VERSION 5.7 ;
BUSBITCHARS "[]" ;
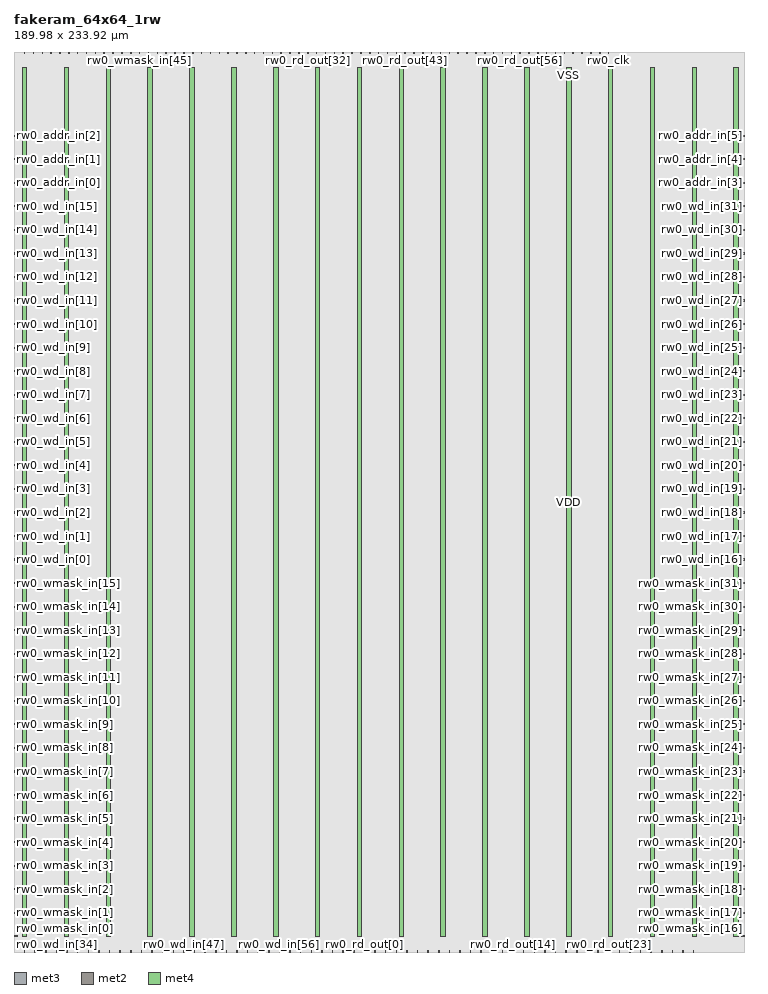
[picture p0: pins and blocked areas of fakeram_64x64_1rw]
MACRO fakeram_64x64_1rw
  FOREIGN fakeram_64x64_1rw 0 0 ;
  SYMMETRY X Y R90 ;
  SIZE 189.980 BY 233.920 ;
  CLASS BLOCK ;
  PIN rw0_wmask_in[0]
    DIRECTION INPUT ;
    USE SIGNAL ;
    SHAPE ABUTMENT ;
    PORT
      LAYER met3 ;
      RECT 0.000 3.930 0.900 4.230 ;
    END
  END rw0_wmask_in[0]
  PIN rw0_wmask_in[1]
    DIRECTION INPUT ;
    USE SIGNAL ;
    SHAPE ABUTMENT ;
    PORT
      LAYER met3 ;
      RECT 0.000 10.050 0.900 10.350 ;
    END
  END rw0_wmask_in[1]
  PIN rw0_wmask_in[2]
    DIRECTION INPUT ;
    USE SIGNAL ;
    SHAPE ABUTMENT ;
    PORT
      LAYER met3 ;
      RECT 0.000 16.170 0.900 16.470 ;
    END
  END rw0_wmask_in[2]
  PIN rw0_wmask_in[3]
    DIRECTION INPUT ;
    USE SIGNAL ;
    SHAPE ABUTMENT ;
    PORT
      LAYER met3 ;
      RECT 0.000 22.290 0.900 22.590 ;
    END
  END rw0_wmask_in[3]
  PIN rw0_wmask_in[4]
    DIRECTION INPUT ;
    USE SIGNAL ;
    SHAPE ABUTMENT ;
    PORT
      LAYER met3 ;
      RECT 0.000 28.410 0.900 28.710 ;
    END
  END rw0_wmask_in[4]
  PIN rw0_wmask_in[5]
    DIRECTION INPUT ;
    USE SIGNAL ;
    SHAPE ABUTMENT ;
    PORT
      LAYER met3 ;
      RECT 0.000 34.530 0.900 34.830 ;
    END
  END rw0_wmask_in[5]
  PIN rw0_wmask_in[6]
    DIRECTION INPUT ;
    USE SIGNAL ;
    SHAPE ABUTMENT ;
    PORT
      LAYER met3 ;
      RECT 0.000 40.650 0.900 40.950 ;
    END
  END rw0_wmask_in[6]
  PIN rw0_wmask_in[7]
    DIRECTION INPUT ;
    USE SIGNAL ;
    SHAPE ABUTMENT ;
    PORT
      LAYER met3 ;
      RECT 0.000 46.770 0.900 47.070 ;
    END
  END rw0_wmask_in[7]
  PIN rw0_wmask_in[8]
    DIRECTION INPUT ;
    USE SIGNAL ;
    SHAPE ABUTMENT ;
    PORT
      LAYER met3 ;
      RECT 0.000 52.890 0.900 53.190 ;
    END
  END rw0_wmask_in[8]
  PIN rw0_wmask_in[9]
    DIRECTION INPUT ;
    USE SIGNAL ;
    SHAPE ABUTMENT ;
    PORT
      LAYER met3 ;
      RECT 0.000 59.010 0.900 59.310 ;
    END
  END rw0_wmask_in[9]
  PIN rw0_wmask_in[10]
    DIRECTION INPUT ;
    USE SIGNAL ;
    SHAPE ABUTMENT ;
    PORT
      LAYER met3 ;
      RECT 0.000 65.130 0.900 65.430 ;
    END
  END rw0_wmask_in[10]
  PIN rw0_wmask_in[11]
    DIRECTION INPUT ;
    USE SIGNAL ;
    SHAPE ABUTMENT ;
    PORT
      LAYER met3 ;
      RECT 0.000 71.250 0.900 71.550 ;
    END
  END rw0_wmask_in[11]
  PIN rw0_wmask_in[12]
    DIRECTION INPUT ;
    USE SIGNAL ;
    SHAPE ABUTMENT ;
    PORT
      LAYER met3 ;
      RECT 0.000 77.370 0.900 77.670 ;
    END
  END rw0_wmask_in[12]
  PIN rw0_wmask_in[13]
    DIRECTION INPUT ;
    USE SIGNAL ;
    SHAPE ABUTMENT ;
    PORT
      LAYER met3 ;
      RECT 0.000 83.490 0.900 83.790 ;
    END
  END rw0_wmask_in[13]
  PIN rw0_wmask_in[14]
    DIRECTION INPUT ;
    USE SIGNAL ;
    SHAPE ABUTMENT ;
    PORT
      LAYER met3 ;
      RECT 0.000 89.610 0.900 89.910 ;
    END
  END rw0_wmask_in[14]
  PIN rw0_wmask_in[15]
    DIRECTION INPUT ;
    USE SIGNAL ;
    SHAPE ABUTMENT ;
    PORT
      LAYER met3 ;
      RECT 0.000 95.730 0.900 96.030 ;
    END
  END rw0_wmask_in[15]
  PIN rw0_wmask_in[16]
    DIRECTION INPUT ;
    USE SIGNAL ;
    SHAPE ABUTMENT ;
    PORT
      LAYER met3 ;
      RECT 189.080 3.930 189.980 4.230 ;
    END
  END rw0_wmask_in[16]
  PIN rw0_wmask_in[17]
    DIRECTION INPUT ;
    USE SIGNAL ;
    SHAPE ABUTMENT ;
    PORT
      LAYER met3 ;
      RECT 189.080 10.050 189.980 10.350 ;
    END
  END rw0_wmask_in[17]
  PIN rw0_wmask_in[18]
    DIRECTION INPUT ;
    USE SIGNAL ;
    SHAPE ABUTMENT ;
    PORT
      LAYER met3 ;
      RECT 189.080 16.170 189.980 16.470 ;
    END
  END rw0_wmask_in[18]
  PIN rw0_wmask_in[19]
    DIRECTION INPUT ;
    USE SIGNAL ;
    SHAPE ABUTMENT ;
    PORT
      LAYER met3 ;
      RECT 189.080 22.290 189.980 22.590 ;
    END
  END rw0_wmask_in[19]
  PIN rw0_wmask_in[20]
    DIRECTION INPUT ;
    USE SIGNAL ;
    SHAPE ABUTMENT ;
    PORT
      LAYER met3 ;
      RECT 189.080 28.410 189.980 28.710 ;
    END
  END rw0_wmask_in[20]
  PIN rw0_wmask_in[21]
    DIRECTION INPUT ;
    USE SIGNAL ;
    SHAPE ABUTMENT ;
    PORT
      LAYER met3 ;
      RECT 189.080 34.530 189.980 34.830 ;
    END
  END rw0_wmask_in[21]
  PIN rw0_wmask_in[22]
    DIRECTION INPUT ;
    USE SIGNAL ;
    SHAPE ABUTMENT ;
    PORT
      LAYER met3 ;
      RECT 189.080 40.650 189.980 40.950 ;
    END
  END rw0_wmask_in[22]
  PIN rw0_wmask_in[23]
    DIRECTION INPUT ;
    USE SIGNAL ;
    SHAPE ABUTMENT ;
    PORT
      LAYER met3 ;
      RECT 189.080 46.770 189.980 47.070 ;
    END
  END rw0_wmask_in[23]
  PIN rw0_wmask_in[24]
    DIRECTION INPUT ;
    USE SIGNAL ;
    SHAPE ABUTMENT ;
    PORT
      LAYER met3 ;
      RECT 189.080 52.890 189.980 53.190 ;
    END
  END rw0_wmask_in[24]
  PIN rw0_wmask_in[25]
    DIRECTION INPUT ;
    USE SIGNAL ;
    SHAPE ABUTMENT ;
    PORT
      LAYER met3 ;
      RECT 189.080 59.010 189.980 59.310 ;
    END
  END rw0_wmask_in[25]
  PIN rw0_wmask_in[26]
    DIRECTION INPUT ;
    USE SIGNAL ;
    SHAPE ABUTMENT ;
    PORT
      LAYER met3 ;
      RECT 189.080 65.130 189.980 65.430 ;
    END
  END rw0_wmask_in[26]
  PIN rw0_wmask_in[27]
    DIRECTION INPUT ;
    USE SIGNAL ;
    SHAPE ABUTMENT ;
    PORT
      LAYER met3 ;
      RECT 189.080 71.250 189.980 71.550 ;
    END
  END rw0_wmask_in[27]
  PIN rw0_wmask_in[28]
    DIRECTION INPUT ;
    USE SIGNAL ;
    SHAPE ABUTMENT ;
    PORT
      LAYER met3 ;
      RECT 189.080 77.370 189.980 77.670 ;
    END
  END rw0_wmask_in[28]
  PIN rw0_wmask_in[29]
    DIRECTION INPUT ;
    USE SIGNAL ;
    SHAPE ABUTMENT ;
    PORT
      LAYER met3 ;
      RECT 189.080 83.490 189.980 83.790 ;
    END
  END rw0_wmask_in[29]
  PIN rw0_wmask_in[30]
    DIRECTION INPUT ;
    USE SIGNAL ;
    SHAPE ABUTMENT ;
    PORT
      LAYER met3 ;
      RECT 189.080 89.610 189.980 89.910 ;
    END
  END rw0_wmask_in[30]
  PIN rw0_wmask_in[31]
    DIRECTION INPUT ;
    USE SIGNAL ;
    SHAPE ABUTMENT ;
    PORT
      LAYER met3 ;
      RECT 189.080 95.730 189.980 96.030 ;
    END
  END rw0_wmask_in[31]
  PIN rw0_wmask_in[32]
    DIRECTION INPUT ;
    USE SIGNAL ;
    SHAPE ABUTMENT ;
    PORT
      LAYER met2 ;
      RECT 2.690 233.500 2.830 233.920 ;
    END
  END rw0_wmask_in[32]
  PIN rw0_wmask_in[33]
    DIRECTION INPUT ;
    USE SIGNAL ;
    SHAPE ABUTMENT ;
    PORT
      LAYER met2 ;
      RECT 4.990 233.500 5.130 233.920 ;
    END
  END rw0_wmask_in[33]
  PIN rw0_wmask_in[34]
    DIRECTION INPUT ;
    USE SIGNAL ;
    SHAPE ABUTMENT ;
    PORT
      LAYER met2 ;
      RECT 7.290 233.500 7.430 233.920 ;
    END
  END rw0_wmask_in[34]
  PIN rw0_wmask_in[35]
    DIRECTION INPUT ;
    USE SIGNAL ;
    SHAPE ABUTMENT ;
    PORT
      LAYER met2 ;
      RECT 9.590 233.500 9.730 233.920 ;
    END
  END rw0_wmask_in[35]
  PIN rw0_wmask_in[36]
    DIRECTION INPUT ;
    USE SIGNAL ;
    SHAPE ABUTMENT ;
    PORT
      LAYER met2 ;
      RECT 11.890 233.500 12.030 233.920 ;
    END
  END rw0_wmask_in[36]
  PIN rw0_wmask_in[37]
    DIRECTION INPUT ;
    USE SIGNAL ;
    SHAPE ABUTMENT ;
    PORT
      LAYER met2 ;
      RECT 14.190 233.500 14.330 233.920 ;
    END
  END rw0_wmask_in[37]
  PIN rw0_wmask_in[38]
    DIRECTION INPUT ;
    USE SIGNAL ;
    SHAPE ABUTMENT ;
    PORT
      LAYER met2 ;
      RECT 16.490 233.500 16.630 233.920 ;
    END
  END rw0_wmask_in[38]
  PIN rw0_wmask_in[39]
    DIRECTION INPUT ;
    USE SIGNAL ;
    SHAPE ABUTMENT ;
    PORT
      LAYER met2 ;
      RECT 18.790 233.500 18.930 233.920 ;
    END
  END rw0_wmask_in[39]
  PIN rw0_wmask_in[40]
    DIRECTION INPUT ;
    USE SIGNAL ;
    SHAPE ABUTMENT ;
    PORT
      LAYER met2 ;
      RECT 21.090 233.500 21.230 233.920 ;
    END
  END rw0_wmask_in[40]
  PIN rw0_wmask_in[41]
    DIRECTION INPUT ;
    USE SIGNAL ;
    SHAPE ABUTMENT ;
    PORT
      LAYER met2 ;
      RECT 23.390 233.500 23.530 233.920 ;
    END
  END rw0_wmask_in[41]
  PIN rw0_wmask_in[42]
    DIRECTION INPUT ;
    USE SIGNAL ;
    SHAPE ABUTMENT ;
    PORT
      LAYER met2 ;
      RECT 25.690 233.500 25.830 233.920 ;
    END
  END rw0_wmask_in[42]
  PIN rw0_wmask_in[43]
    DIRECTION INPUT ;
    USE SIGNAL ;
    SHAPE ABUTMENT ;
    PORT
      LAYER met2 ;
      RECT 27.990 233.500 28.130 233.920 ;
    END
  END rw0_wmask_in[43]
  PIN rw0_wmask_in[44]
    DIRECTION INPUT ;
    USE SIGNAL ;
    SHAPE ABUTMENT ;
    PORT
      LAYER met2 ;
      RECT 30.290 233.500 30.430 233.920 ;
    END
  END rw0_wmask_in[44]
  PIN rw0_wmask_in[45]
    DIRECTION INPUT ;
    USE SIGNAL ;
    SHAPE ABUTMENT ;
    PORT
      LAYER met2 ;
      RECT 32.590 233.500 32.730 233.920 ;
    END
  END rw0_wmask_in[45]
  PIN rw0_wmask_in[46]
    DIRECTION INPUT ;
    USE SIGNAL ;
    SHAPE ABUTMENT ;
    PORT
      LAYER met2 ;
      RECT 34.890 233.500 35.030 233.920 ;
    END
  END rw0_wmask_in[46]
  PIN rw0_wmask_in[47]
    DIRECTION INPUT ;
    USE SIGNAL ;
    SHAPE ABUTMENT ;
    PORT
      LAYER met2 ;
      RECT 37.190 233.500 37.330 233.920 ;
    END
  END rw0_wmask_in[47]
  PIN rw0_wmask_in[48]
    DIRECTION INPUT ;
    USE SIGNAL ;
    SHAPE ABUTMENT ;
    PORT
      LAYER met2 ;
      RECT 39.490 233.500 39.630 233.920 ;
    END
  END rw0_wmask_in[48]
  PIN rw0_wmask_in[49]
    DIRECTION INPUT ;
    USE SIGNAL ;
    SHAPE ABUTMENT ;
    PORT
      LAYER met2 ;
      RECT 41.790 233.500 41.930 233.920 ;
    END
  END rw0_wmask_in[49]
  PIN rw0_wmask_in[50]
    DIRECTION INPUT ;
    USE SIGNAL ;
    SHAPE ABUTMENT ;
    PORT
      LAYER met2 ;
      RECT 44.090 233.500 44.230 233.920 ;
    END
  END rw0_wmask_in[50]
  PIN rw0_wmask_in[51]
    DIRECTION INPUT ;
    USE SIGNAL ;
    SHAPE ABUTMENT ;
    PORT
      LAYER met2 ;
      RECT 46.390 233.500 46.530 233.920 ;
    END
  END rw0_wmask_in[51]
  PIN rw0_wmask_in[52]
    DIRECTION INPUT ;
    USE SIGNAL ;
    SHAPE ABUTMENT ;
    PORT
      LAYER met2 ;
      RECT 48.690 233.500 48.830 233.920 ;
    END
  END rw0_wmask_in[52]
  PIN rw0_wmask_in[53]
    DIRECTION INPUT ;
    USE SIGNAL ;
    SHAPE ABUTMENT ;
    PORT
      LAYER met2 ;
      RECT 50.990 233.500 51.130 233.920 ;
    END
  END rw0_wmask_in[53]
  PIN rw0_wmask_in[54]
    DIRECTION INPUT ;
    USE SIGNAL ;
    SHAPE ABUTMENT ;
    PORT
      LAYER met2 ;
      RECT 53.290 233.500 53.430 233.920 ;
    END
  END rw0_wmask_in[54]
  PIN rw0_wmask_in[55]
    DIRECTION INPUT ;
    USE SIGNAL ;
    SHAPE ABUTMENT ;
    PORT
      LAYER met2 ;
      RECT 55.590 233.500 55.730 233.920 ;
    END
  END rw0_wmask_in[55]
  PIN rw0_wmask_in[56]
    DIRECTION INPUT ;
    USE SIGNAL ;
    SHAPE ABUTMENT ;
    PORT
      LAYER met2 ;
      RECT 57.890 233.500 58.030 233.920 ;
    END
  END rw0_wmask_in[56]
  PIN rw0_wmask_in[57]
    DIRECTION INPUT ;
    USE SIGNAL ;
    SHAPE ABUTMENT ;
    PORT
      LAYER met2 ;
      RECT 60.190 233.500 60.330 233.920 ;
    END
  END rw0_wmask_in[57]
  PIN rw0_wmask_in[58]
    DIRECTION INPUT ;
    USE SIGNAL ;
    SHAPE ABUTMENT ;
    PORT
      LAYER met2 ;
      RECT 62.490 233.500 62.630 233.920 ;
    END
  END rw0_wmask_in[58]
  PIN rw0_wmask_in[59]
    DIRECTION INPUT ;
    USE SIGNAL ;
    SHAPE ABUTMENT ;
    PORT
      LAYER met2 ;
      RECT 64.790 233.500 64.930 233.920 ;
    END
  END rw0_wmask_in[59]
  PIN rw0_wmask_in[60]
    DIRECTION INPUT ;
    USE SIGNAL ;
    SHAPE ABUTMENT ;
    PORT
      LAYER met2 ;
      RECT 67.090 233.500 67.230 233.920 ;
    END
  END rw0_wmask_in[60]
  PIN rw0_wmask_in[61]
    DIRECTION INPUT ;
    USE SIGNAL ;
    SHAPE ABUTMENT ;
    PORT
      LAYER met2 ;
      RECT 69.390 233.500 69.530 233.920 ;
    END
  END rw0_wmask_in[61]
  PIN rw0_wmask_in[62]
    DIRECTION INPUT ;
    USE SIGNAL ;
    SHAPE ABUTMENT ;
    PORT
      LAYER met2 ;
      RECT 71.690 233.500 71.830 233.920 ;
    END
  END rw0_wmask_in[62]
  PIN rw0_wmask_in[63]
    DIRECTION INPUT ;
    USE SIGNAL ;
    SHAPE ABUTMENT ;
    PORT
      LAYER met2 ;
      RECT 73.990 233.500 74.130 233.920 ;
    END
  END rw0_wmask_in[63]
  PIN rw0_wd_in[0]
    DIRECTION INPUT ;
    USE SIGNAL ;
    SHAPE ABUTMENT ;
    PORT
      LAYER met3 ;
      RECT 0.000 101.850 0.900 102.150 ;
    END
  END rw0_wd_in[0]
  PIN rw0_wd_in[1]
    DIRECTION INPUT ;
    USE SIGNAL ;
    SHAPE ABUTMENT ;
    PORT
      LAYER met3 ;
      RECT 0.000 107.970 0.900 108.270 ;
    END
  END rw0_wd_in[1]
  PIN rw0_wd_in[2]
    DIRECTION INPUT ;
    USE SIGNAL ;
    SHAPE ABUTMENT ;
    PORT
      LAYER met3 ;
      RECT 0.000 114.090 0.900 114.390 ;
    END
  END rw0_wd_in[2]
  PIN rw0_wd_in[3]
    DIRECTION INPUT ;
    USE SIGNAL ;
    SHAPE ABUTMENT ;
    PORT
      LAYER met3 ;
      RECT 0.000 120.210 0.900 120.510 ;
    END
  END rw0_wd_in[3]
  PIN rw0_wd_in[4]
    DIRECTION INPUT ;
    USE SIGNAL ;
    SHAPE ABUTMENT ;
    PORT
      LAYER met3 ;
      RECT 0.000 126.330 0.900 126.630 ;
    END
  END rw0_wd_in[4]
  PIN rw0_wd_in[5]
    DIRECTION INPUT ;
    USE SIGNAL ;
    SHAPE ABUTMENT ;
    PORT
      LAYER met3 ;
      RECT 0.000 132.450 0.900 132.750 ;
    END
  END rw0_wd_in[5]
  PIN rw0_wd_in[6]
    DIRECTION INPUT ;
    USE SIGNAL ;
    SHAPE ABUTMENT ;
    PORT
      LAYER met3 ;
      RECT 0.000 138.570 0.900 138.870 ;
    END
  END rw0_wd_in[6]
  PIN rw0_wd_in[7]
    DIRECTION INPUT ;
    USE SIGNAL ;
    SHAPE ABUTMENT ;
    PORT
      LAYER met3 ;
      RECT 0.000 144.690 0.900 144.990 ;
    END
  END rw0_wd_in[7]
  PIN rw0_wd_in[8]
    DIRECTION INPUT ;
    USE SIGNAL ;
    SHAPE ABUTMENT ;
    PORT
      LAYER met3 ;
      RECT 0.000 150.810 0.900 151.110 ;
    END
  END rw0_wd_in[8]
  PIN rw0_wd_in[9]
    DIRECTION INPUT ;
    USE SIGNAL ;
    SHAPE ABUTMENT ;
    PORT
      LAYER met3 ;
      RECT 0.000 156.930 0.900 157.230 ;
    END
  END rw0_wd_in[9]
  PIN rw0_wd_in[10]
    DIRECTION INPUT ;
    USE SIGNAL ;
    SHAPE ABUTMENT ;
    PORT
      LAYER met3 ;
      RECT 0.000 163.050 0.900 163.350 ;
    END
  END rw0_wd_in[10]
  PIN rw0_wd_in[11]
    DIRECTION INPUT ;
    USE SIGNAL ;
    SHAPE ABUTMENT ;
    PORT
      LAYER met3 ;
      RECT 0.000 169.170 0.900 169.470 ;
    END
  END rw0_wd_in[11]
  PIN rw0_wd_in[12]
    DIRECTION INPUT ;
    USE SIGNAL ;
    SHAPE ABUTMENT ;
    PORT
      LAYER met3 ;
      RECT 0.000 175.290 0.900 175.590 ;
    END
  END rw0_wd_in[12]
  PIN rw0_wd_in[13]
    DIRECTION INPUT ;
    USE SIGNAL ;
    SHAPE ABUTMENT ;
    PORT
      LAYER met3 ;
      RECT 0.000 181.410 0.900 181.710 ;
    END
  END rw0_wd_in[13]
  PIN rw0_wd_in[14]
    DIRECTION INPUT ;
    USE SIGNAL ;
    SHAPE ABUTMENT ;
    PORT
      LAYER met3 ;
      RECT 0.000 187.530 0.900 187.830 ;
    END
  END rw0_wd_in[14]
  PIN rw0_wd_in[15]
    DIRECTION INPUT ;
    USE SIGNAL ;
    SHAPE ABUTMENT ;
    PORT
      LAYER met3 ;
      RECT 0.000 193.650 0.900 193.950 ;
    END
  END rw0_wd_in[15]
  PIN rw0_wd_in[16]
    DIRECTION INPUT ;
    USE SIGNAL ;
    SHAPE ABUTMENT ;
    PORT
      LAYER met3 ;
      RECT 189.080 101.850 189.980 102.150 ;
    END
  END rw0_wd_in[16]
  PIN rw0_wd_in[17]
    DIRECTION INPUT ;
    USE SIGNAL ;
    SHAPE ABUTMENT ;
    PORT
      LAYER met3 ;
      RECT 189.080 107.970 189.980 108.270 ;
    END
  END rw0_wd_in[17]
  PIN rw0_wd_in[18]
    DIRECTION INPUT ;
    USE SIGNAL ;
    SHAPE ABUTMENT ;
    PORT
      LAYER met3 ;
      RECT 189.080 114.090 189.980 114.390 ;
    END
  END rw0_wd_in[18]
  PIN rw0_wd_in[19]
    DIRECTION INPUT ;
    USE SIGNAL ;
    SHAPE ABUTMENT ;
    PORT
      LAYER met3 ;
      RECT 189.080 120.210 189.980 120.510 ;
    END
  END rw0_wd_in[19]
  PIN rw0_wd_in[20]
    DIRECTION INPUT ;
    USE SIGNAL ;
    SHAPE ABUTMENT ;
    PORT
      LAYER met3 ;
      RECT 189.080 126.330 189.980 126.630 ;
    END
  END rw0_wd_in[20]
  PIN rw0_wd_in[21]
    DIRECTION INPUT ;
    USE SIGNAL ;
    SHAPE ABUTMENT ;
    PORT
      LAYER met3 ;
      RECT 189.080 132.450 189.980 132.750 ;
    END
  END rw0_wd_in[21]
  PIN rw0_wd_in[22]
    DIRECTION INPUT ;
    USE SIGNAL ;
    SHAPE ABUTMENT ;
    PORT
      LAYER met3 ;
      RECT 189.080 138.570 189.980 138.870 ;
    END
  END rw0_wd_in[22]
  PIN rw0_wd_in[23]
    DIRECTION INPUT ;
    USE SIGNAL ;
    SHAPE ABUTMENT ;
    PORT
      LAYER met3 ;
      RECT 189.080 144.690 189.980 144.990 ;
    END
  END rw0_wd_in[23]
  PIN rw0_wd_in[24]
    DIRECTION INPUT ;
    USE SIGNAL ;
    SHAPE ABUTMENT ;
    PORT
      LAYER met3 ;
      RECT 189.080 150.810 189.980 151.110 ;
    END
  END rw0_wd_in[24]
  PIN rw0_wd_in[25]
    DIRECTION INPUT ;
    USE SIGNAL ;
    SHAPE ABUTMENT ;
    PORT
      LAYER met3 ;
      RECT 189.080 156.930 189.980 157.230 ;
    END
  END rw0_wd_in[25]
  PIN rw0_wd_in[26]
    DIRECTION INPUT ;
    USE SIGNAL ;
    SHAPE ABUTMENT ;
    PORT
      LAYER met3 ;
      RECT 189.080 163.050 189.980 163.350 ;
    END
  END rw0_wd_in[26]
  PIN rw0_wd_in[27]
    DIRECTION INPUT ;
    USE SIGNAL ;
    SHAPE ABUTMENT ;
    PORT
      LAYER met3 ;
      RECT 189.080 169.170 189.980 169.470 ;
    END
  END rw0_wd_in[27]
  PIN rw0_wd_in[28]
    DIRECTION INPUT ;
    USE SIGNAL ;
    SHAPE ABUTMENT ;
    PORT
      LAYER met3 ;
      RECT 189.080 175.290 189.980 175.590 ;
    END
  END rw0_wd_in[28]
  PIN rw0_wd_in[29]
    DIRECTION INPUT ;
    USE SIGNAL ;
    SHAPE ABUTMENT ;
    PORT
      LAYER met3 ;
      RECT 189.080 181.410 189.980 181.710 ;
    END
  END rw0_wd_in[29]
  PIN rw0_wd_in[30]
    DIRECTION INPUT ;
    USE SIGNAL ;
    SHAPE ABUTMENT ;
    PORT
      LAYER met3 ;
      RECT 189.080 187.530 189.980 187.830 ;
    END
  END rw0_wd_in[30]
  PIN rw0_wd_in[31]
    DIRECTION INPUT ;
    USE SIGNAL ;
    SHAPE ABUTMENT ;
    PORT
      LAYER met3 ;
      RECT 189.080 193.650 189.980 193.950 ;
    END
  END rw0_wd_in[31]
  PIN rw0_wd_in[32]
    DIRECTION OUTPUT ;
    USE SIGNAL ;
    SHAPE ABUTMENT ;
    PORT
      LAYER met2 ;
      RECT 2.690 0.000 2.830 0.420 ;
    END
  END rw0_wd_in[32]
  PIN rw0_wd_in[33]
    DIRECTION OUTPUT ;
    USE SIGNAL ;
    SHAPE ABUTMENT ;
    PORT
      LAYER met2 ;
      RECT 5.450 0.000 5.590 0.420 ;
    END
  END rw0_wd_in[33]
  PIN rw0_wd_in[34]
    DIRECTION OUTPUT ;
    USE SIGNAL ;
    SHAPE ABUTMENT ;
    PORT
      LAYER met2 ;
      RECT 8.210 0.000 8.350 0.420 ;
    END
  END rw0_wd_in[34]
  PIN rw0_wd_in[35]
    DIRECTION OUTPUT ;
    USE SIGNAL ;
    SHAPE ABUTMENT ;
    PORT
      LAYER met2 ;
      RECT 10.970 0.000 11.110 0.420 ;
    END
  END rw0_wd_in[35]
  PIN rw0_wd_in[36]
    DIRECTION OUTPUT ;
    USE SIGNAL ;
    SHAPE ABUTMENT ;
    PORT
      LAYER met2 ;
      RECT 13.730 0.000 13.870 0.420 ;
    END
  END rw0_wd_in[36]
  PIN rw0_wd_in[37]
    DIRECTION OUTPUT ;
    USE SIGNAL ;
    SHAPE ABUTMENT ;
    PORT
      LAYER met2 ;
      RECT 16.490 0.000 16.630 0.420 ;
    END
  END rw0_wd_in[37]
  PIN rw0_wd_in[38]
    DIRECTION OUTPUT ;
    USE SIGNAL ;
    SHAPE ABUTMENT ;
    PORT
      LAYER met2 ;
      RECT 19.250 0.000 19.390 0.420 ;
    END
  END rw0_wd_in[38]
  PIN rw0_wd_in[39]
    DIRECTION OUTPUT ;
    USE SIGNAL ;
    SHAPE ABUTMENT ;
    PORT
      LAYER met2 ;
      RECT 22.010 0.000 22.150 0.420 ;
    END
  END rw0_wd_in[39]
  PIN rw0_wd_in[40]
    DIRECTION OUTPUT ;
    USE SIGNAL ;
    SHAPE ABUTMENT ;
    PORT
      LAYER met2 ;
      RECT 24.770 0.000 24.910 0.420 ;
    END
  END rw0_wd_in[40]
  PIN rw0_wd_in[41]
    DIRECTION OUTPUT ;
    USE SIGNAL ;
    SHAPE ABUTMENT ;
    PORT
      LAYER met2 ;
      RECT 27.530 0.000 27.670 0.420 ;
    END
  END rw0_wd_in[41]
  PIN rw0_wd_in[42]
    DIRECTION OUTPUT ;
    USE SIGNAL ;
    SHAPE ABUTMENT ;
    PORT
      LAYER met2 ;
      RECT 30.290 0.000 30.430 0.420 ;
    END
  END rw0_wd_in[42]
  PIN rw0_wd_in[43]
    DIRECTION OUTPUT ;
    USE SIGNAL ;
    SHAPE ABUTMENT ;
    PORT
      LAYER met2 ;
      RECT 33.050 0.000 33.190 0.420 ;
    END
  END rw0_wd_in[43]
  PIN rw0_wd_in[44]
    DIRECTION OUTPUT ;
    USE SIGNAL ;
    SHAPE ABUTMENT ;
    PORT
      LAYER met2 ;
      RECT 35.810 0.000 35.950 0.420 ;
    END
  END rw0_wd_in[44]
  PIN rw0_wd_in[45]
    DIRECTION OUTPUT ;
    USE SIGNAL ;
    SHAPE ABUTMENT ;
    PORT
      LAYER met2 ;
      RECT 38.570 0.000 38.710 0.420 ;
    END
  END rw0_wd_in[45]
  PIN rw0_wd_in[46]
    DIRECTION OUTPUT ;
    USE SIGNAL ;
    SHAPE ABUTMENT ;
    PORT
      LAYER met2 ;
      RECT 41.330 0.000 41.470 0.420 ;
    END
  END rw0_wd_in[46]
  PIN rw0_wd_in[47]
    DIRECTION OUTPUT ;
    USE SIGNAL ;
    SHAPE ABUTMENT ;
    PORT
      LAYER met2 ;
      RECT 44.090 0.000 44.230 0.420 ;
    END
  END rw0_wd_in[47]
  PIN rw0_wd_in[48]
    DIRECTION OUTPUT ;
    USE SIGNAL ;
    SHAPE ABUTMENT ;
    PORT
      LAYER met2 ;
      RECT 46.850 0.000 46.990 0.420 ;
    END
  END rw0_wd_in[48]
  PIN rw0_wd_in[49]
    DIRECTION OUTPUT ;
    USE SIGNAL ;
    SHAPE ABUTMENT ;
    PORT
      LAYER met2 ;
      RECT 49.610 0.000 49.750 0.420 ;
    END
  END rw0_wd_in[49]
  PIN rw0_wd_in[50]
    DIRECTION OUTPUT ;
    USE SIGNAL ;
    SHAPE ABUTMENT ;
    PORT
      LAYER met2 ;
      RECT 52.370 0.000 52.510 0.420 ;
    END
  END rw0_wd_in[50]
  PIN rw0_wd_in[51]
    DIRECTION OUTPUT ;
    USE SIGNAL ;
    SHAPE ABUTMENT ;
    PORT
      LAYER met2 ;
      RECT 55.130 0.000 55.270 0.420 ;
    END
  END rw0_wd_in[51]
  PIN rw0_wd_in[52]
    DIRECTION OUTPUT ;
    USE SIGNAL ;
    SHAPE ABUTMENT ;
    PORT
      LAYER met2 ;
      RECT 57.890 0.000 58.030 0.420 ;
    END
  END rw0_wd_in[52]
  PIN rw0_wd_in[53]
    DIRECTION OUTPUT ;
    USE SIGNAL ;
    SHAPE ABUTMENT ;
    PORT
      LAYER met2 ;
      RECT 60.650 0.000 60.790 0.420 ;
    END
  END rw0_wd_in[53]
  PIN rw0_wd_in[54]
    DIRECTION OUTPUT ;
    USE SIGNAL ;
    SHAPE ABUTMENT ;
    PORT
      LAYER met2 ;
      RECT 63.410 0.000 63.550 0.420 ;
    END
  END rw0_wd_in[54]
  PIN rw0_wd_in[55]
    DIRECTION OUTPUT ;
    USE SIGNAL ;
    SHAPE ABUTMENT ;
    PORT
      LAYER met2 ;
      RECT 66.170 0.000 66.310 0.420 ;
    END
  END rw0_wd_in[55]
  PIN rw0_wd_in[56]
    DIRECTION OUTPUT ;
    USE SIGNAL ;
    SHAPE ABUTMENT ;
    PORT
      LAYER met2 ;
      RECT 68.930 0.000 69.070 0.420 ;
    END
  END rw0_wd_in[56]
  PIN rw0_wd_in[57]
    DIRECTION OUTPUT ;
    USE SIGNAL ;
    SHAPE ABUTMENT ;
    PORT
      LAYER met2 ;
      RECT 71.690 0.000 71.830 0.420 ;
    END
  END rw0_wd_in[57]
  PIN rw0_wd_in[58]
    DIRECTION OUTPUT ;
    USE SIGNAL ;
    SHAPE ABUTMENT ;
    PORT
      LAYER met2 ;
      RECT 74.450 0.000 74.590 0.420 ;
    END
  END rw0_wd_in[58]
  PIN rw0_wd_in[59]
    DIRECTION OUTPUT ;
    USE SIGNAL ;
    SHAPE ABUTMENT ;
    PORT
      LAYER met2 ;
      RECT 77.210 0.000 77.350 0.420 ;
    END
  END rw0_wd_in[59]
  PIN rw0_wd_in[60]
    DIRECTION OUTPUT ;
    USE SIGNAL ;
    SHAPE ABUTMENT ;
    PORT
      LAYER met2 ;
      RECT 79.970 0.000 80.110 0.420 ;
    END
  END rw0_wd_in[60]
  PIN rw0_wd_in[61]
    DIRECTION OUTPUT ;
    USE SIGNAL ;
    SHAPE ABUTMENT ;
    PORT
      LAYER met2 ;
      RECT 82.730 0.000 82.870 0.420 ;
    END
  END rw0_wd_in[61]
  PIN rw0_wd_in[62]
    DIRECTION OUTPUT ;
    USE SIGNAL ;
    SHAPE ABUTMENT ;
    PORT
      LAYER met2 ;
      RECT 85.490 0.000 85.630 0.420 ;
    END
  END rw0_wd_in[62]
  PIN rw0_wd_in[63]
    DIRECTION OUTPUT ;
    USE SIGNAL ;
    SHAPE ABUTMENT ;
    PORT
      LAYER met2 ;
      RECT 88.250 0.000 88.390 0.420 ;
    END
  END rw0_wd_in[63]
  PIN rw0_rd_out[0]
    DIRECTION OUTPUT ;
    USE SIGNAL ;
    SHAPE ABUTMENT ;
    PORT
      LAYER met2 ;
      RECT 91.010 0.000 91.150 0.420 ;
    END
  END rw0_rd_out[0]
  PIN rw0_rd_out[1]
    DIRECTION OUTPUT ;
    USE SIGNAL ;
    SHAPE ABUTMENT ;
    PORT
      LAYER met2 ;
      RECT 93.770 0.000 93.910 0.420 ;
    END
  END rw0_rd_out[1]
  PIN rw0_rd_out[2]
    DIRECTION OUTPUT ;
    USE SIGNAL ;
    SHAPE ABUTMENT ;
    PORT
      LAYER met2 ;
      RECT 96.530 0.000 96.670 0.420 ;
    END
  END rw0_rd_out[2]
  PIN rw0_rd_out[3]
    DIRECTION OUTPUT ;
    USE SIGNAL ;
    SHAPE ABUTMENT ;
    PORT
      LAYER met2 ;
      RECT 99.290 0.000 99.430 0.420 ;
    END
  END rw0_rd_out[3]
  PIN rw0_rd_out[4]
    DIRECTION OUTPUT ;
    USE SIGNAL ;
    SHAPE ABUTMENT ;
    PORT
      LAYER met2 ;
      RECT 102.050 0.000 102.190 0.420 ;
    END
  END rw0_rd_out[4]
  PIN rw0_rd_out[5]
    DIRECTION OUTPUT ;
    USE SIGNAL ;
    SHAPE ABUTMENT ;
    PORT
      LAYER met2 ;
      RECT 104.810 0.000 104.950 0.420 ;
    END
  END rw0_rd_out[5]
  PIN rw0_rd_out[6]
    DIRECTION OUTPUT ;
    USE SIGNAL ;
    SHAPE ABUTMENT ;
    PORT
      LAYER met2 ;
      RECT 107.570 0.000 107.710 0.420 ;
    END
  END rw0_rd_out[6]
  PIN rw0_rd_out[7]
    DIRECTION OUTPUT ;
    USE SIGNAL ;
    SHAPE ABUTMENT ;
    PORT
      LAYER met2 ;
      RECT 110.330 0.000 110.470 0.420 ;
    END
  END rw0_rd_out[7]
  PIN rw0_rd_out[8]
    DIRECTION OUTPUT ;
    USE SIGNAL ;
    SHAPE ABUTMENT ;
    PORT
      LAYER met2 ;
      RECT 113.090 0.000 113.230 0.420 ;
    END
  END rw0_rd_out[8]
  PIN rw0_rd_out[9]
    DIRECTION OUTPUT ;
    USE SIGNAL ;
    SHAPE ABUTMENT ;
    PORT
      LAYER met2 ;
      RECT 115.850 0.000 115.990 0.420 ;
    END
  END rw0_rd_out[9]
  PIN rw0_rd_out[10]
    DIRECTION OUTPUT ;
    USE SIGNAL ;
    SHAPE ABUTMENT ;
    PORT
      LAYER met2 ;
      RECT 118.610 0.000 118.750 0.420 ;
    END
  END rw0_rd_out[10]
  PIN rw0_rd_out[11]
    DIRECTION OUTPUT ;
    USE SIGNAL ;
    SHAPE ABUTMENT ;
    PORT
      LAYER met2 ;
      RECT 121.370 0.000 121.510 0.420 ;
    END
  END rw0_rd_out[11]
  PIN rw0_rd_out[12]
    DIRECTION OUTPUT ;
    USE SIGNAL ;
    SHAPE ABUTMENT ;
    PORT
      LAYER met2 ;
      RECT 124.130 0.000 124.270 0.420 ;
    END
  END rw0_rd_out[12]
  PIN rw0_rd_out[13]
    DIRECTION OUTPUT ;
    USE SIGNAL ;
    SHAPE ABUTMENT ;
    PORT
      LAYER met2 ;
      RECT 126.890 0.000 127.030 0.420 ;
    END
  END rw0_rd_out[13]
  PIN rw0_rd_out[14]
    DIRECTION OUTPUT ;
    USE SIGNAL ;
    SHAPE ABUTMENT ;
    PORT
      LAYER met2 ;
      RECT 129.650 0.000 129.790 0.420 ;
    END
  END rw0_rd_out[14]
  PIN rw0_rd_out[15]
    DIRECTION OUTPUT ;
    USE SIGNAL ;
    SHAPE ABUTMENT ;
    PORT
      LAYER met2 ;
      RECT 132.410 0.000 132.550 0.420 ;
    END
  END rw0_rd_out[15]
  PIN rw0_rd_out[16]
    DIRECTION OUTPUT ;
    USE SIGNAL ;
    SHAPE ABUTMENT ;
    PORT
      LAYER met2 ;
      RECT 135.170 0.000 135.310 0.420 ;
    END
  END rw0_rd_out[16]
  PIN rw0_rd_out[17]
    DIRECTION OUTPUT ;
    USE SIGNAL ;
    SHAPE ABUTMENT ;
    PORT
      LAYER met2 ;
      RECT 137.930 0.000 138.070 0.420 ;
    END
  END rw0_rd_out[17]
  PIN rw0_rd_out[18]
    DIRECTION OUTPUT ;
    USE SIGNAL ;
    SHAPE ABUTMENT ;
    PORT
      LAYER met2 ;
      RECT 140.690 0.000 140.830 0.420 ;
    END
  END rw0_rd_out[18]
  PIN rw0_rd_out[19]
    DIRECTION OUTPUT ;
    USE SIGNAL ;
    SHAPE ABUTMENT ;
    PORT
      LAYER met2 ;
      RECT 143.450 0.000 143.590 0.420 ;
    END
  END rw0_rd_out[19]
  PIN rw0_rd_out[20]
    DIRECTION OUTPUT ;
    USE SIGNAL ;
    SHAPE ABUTMENT ;
    PORT
      LAYER met2 ;
      RECT 146.210 0.000 146.350 0.420 ;
    END
  END rw0_rd_out[20]
  PIN rw0_rd_out[21]
    DIRECTION OUTPUT ;
    USE SIGNAL ;
    SHAPE ABUTMENT ;
    PORT
      LAYER met2 ;
      RECT 148.970 0.000 149.110 0.420 ;
    END
  END rw0_rd_out[21]
  PIN rw0_rd_out[22]
    DIRECTION OUTPUT ;
    USE SIGNAL ;
    SHAPE ABUTMENT ;
    PORT
      LAYER met2 ;
      RECT 151.730 0.000 151.870 0.420 ;
    END
  END rw0_rd_out[22]
  PIN rw0_rd_out[23]
    DIRECTION OUTPUT ;
    USE SIGNAL ;
    SHAPE ABUTMENT ;
    PORT
      LAYER met2 ;
      RECT 154.490 0.000 154.630 0.420 ;
    END
  END rw0_rd_out[23]
  PIN rw0_rd_out[24]
    DIRECTION OUTPUT ;
    USE SIGNAL ;
    SHAPE ABUTMENT ;
    PORT
      LAYER met2 ;
      RECT 157.250 0.000 157.390 0.420 ;
    END
  END rw0_rd_out[24]
  PIN rw0_rd_out[25]
    DIRECTION OUTPUT ;
    USE SIGNAL ;
    SHAPE ABUTMENT ;
    PORT
      LAYER met2 ;
      RECT 160.010 0.000 160.150 0.420 ;
    END
  END rw0_rd_out[25]
  PIN rw0_rd_out[26]
    DIRECTION OUTPUT ;
    USE SIGNAL ;
    SHAPE ABUTMENT ;
    PORT
      LAYER met2 ;
      RECT 162.770 0.000 162.910 0.420 ;
    END
  END rw0_rd_out[26]
  PIN rw0_rd_out[27]
    DIRECTION OUTPUT ;
    USE SIGNAL ;
    SHAPE ABUTMENT ;
    PORT
      LAYER met2 ;
      RECT 165.530 0.000 165.670 0.420 ;
    END
  END rw0_rd_out[27]
  PIN rw0_rd_out[28]
    DIRECTION OUTPUT ;
    USE SIGNAL ;
    SHAPE ABUTMENT ;
    PORT
      LAYER met2 ;
      RECT 168.290 0.000 168.430 0.420 ;
    END
  END rw0_rd_out[28]
  PIN rw0_rd_out[29]
    DIRECTION OUTPUT ;
    USE SIGNAL ;
    SHAPE ABUTMENT ;
    PORT
      LAYER met2 ;
      RECT 171.050 0.000 171.190 0.420 ;
    END
  END rw0_rd_out[29]
  PIN rw0_rd_out[30]
    DIRECTION OUTPUT ;
    USE SIGNAL ;
    SHAPE ABUTMENT ;
    PORT
      LAYER met2 ;
      RECT 173.810 0.000 173.950 0.420 ;
    END
  END rw0_rd_out[30]
  PIN rw0_rd_out[31]
    DIRECTION OUTPUT ;
    USE SIGNAL ;
    SHAPE ABUTMENT ;
    PORT
      LAYER met2 ;
      RECT 176.570 0.000 176.710 0.420 ;
    END
  END rw0_rd_out[31]
  PIN rw0_rd_out[32]
    DIRECTION OUTPUT ;
    USE SIGNAL ;
    SHAPE ABUTMENT ;
    PORT
      LAYER met2 ;
      RECT 76.290 233.500 76.430 233.920 ;
    END
  END rw0_rd_out[32]
  PIN rw0_rd_out[33]
    DIRECTION OUTPUT ;
    USE SIGNAL ;
    SHAPE ABUTMENT ;
    PORT
      LAYER met2 ;
      RECT 78.590 233.500 78.730 233.920 ;
    END
  END rw0_rd_out[33]
  PIN rw0_rd_out[34]
    DIRECTION OUTPUT ;
    USE SIGNAL ;
    SHAPE ABUTMENT ;
    PORT
      LAYER met2 ;
      RECT 80.890 233.500 81.030 233.920 ;
    END
  END rw0_rd_out[34]
  PIN rw0_rd_out[35]
    DIRECTION OUTPUT ;
    USE SIGNAL ;
    SHAPE ABUTMENT ;
    PORT
      LAYER met2 ;
      RECT 83.190 233.500 83.330 233.920 ;
    END
  END rw0_rd_out[35]
  PIN rw0_rd_out[36]
    DIRECTION OUTPUT ;
    USE SIGNAL ;
    SHAPE ABUTMENT ;
    PORT
      LAYER met2 ;
      RECT 85.490 233.500 85.630 233.920 ;
    END
  END rw0_rd_out[36]
  PIN rw0_rd_out[37]
    DIRECTION OUTPUT ;
    USE SIGNAL ;
    SHAPE ABUTMENT ;
    PORT
      LAYER met2 ;
      RECT 87.790 233.500 87.930 233.920 ;
    END
  END rw0_rd_out[37]
  PIN rw0_rd_out[38]
    DIRECTION OUTPUT ;
    USE SIGNAL ;
    SHAPE ABUTMENT ;
    PORT
      LAYER met2 ;
      RECT 90.090 233.500 90.230 233.920 ;
    END
  END rw0_rd_out[38]
  PIN rw0_rd_out[39]
    DIRECTION OUTPUT ;
    USE SIGNAL ;
    SHAPE ABUTMENT ;
    PORT
      LAYER met2 ;
      RECT 92.390 233.500 92.530 233.920 ;
    END
  END rw0_rd_out[39]
  PIN rw0_rd_out[40]
    DIRECTION OUTPUT ;
    USE SIGNAL ;
    SHAPE ABUTMENT ;
    PORT
      LAYER met2 ;
      RECT 94.690 233.500 94.830 233.920 ;
    END
  END rw0_rd_out[40]
  PIN rw0_rd_out[41]
    DIRECTION OUTPUT ;
    USE SIGNAL ;
    SHAPE ABUTMENT ;
    PORT
      LAYER met2 ;
      RECT 96.990 233.500 97.130 233.920 ;
    END
  END rw0_rd_out[41]
  PIN rw0_rd_out[42]
    DIRECTION OUTPUT ;
    USE SIGNAL ;
    SHAPE ABUTMENT ;
    PORT
      LAYER met2 ;
      RECT 99.290 233.500 99.430 233.920 ;
    END
  END rw0_rd_out[42]
  PIN rw0_rd_out[43]
    DIRECTION OUTPUT ;
    USE SIGNAL ;
    SHAPE ABUTMENT ;
    PORT
      LAYER met2 ;
      RECT 101.590 233.500 101.730 233.920 ;
    END
  END rw0_rd_out[43]
  PIN rw0_rd_out[44]
    DIRECTION OUTPUT ;
    USE SIGNAL ;
    SHAPE ABUTMENT ;
    PORT
      LAYER met2 ;
      RECT 103.890 233.500 104.030 233.920 ;
    END
  END rw0_rd_out[44]
  PIN rw0_rd_out[45]
    DIRECTION OUTPUT ;
    USE SIGNAL ;
    SHAPE ABUTMENT ;
    PORT
      LAYER met2 ;
      RECT 106.190 233.500 106.330 233.920 ;
    END
  END rw0_rd_out[45]
  PIN rw0_rd_out[46]
    DIRECTION OUTPUT ;
    USE SIGNAL ;
    SHAPE ABUTMENT ;
    PORT
      LAYER met2 ;
      RECT 108.490 233.500 108.630 233.920 ;
    END
  END rw0_rd_out[46]
  PIN rw0_rd_out[47]
    DIRECTION OUTPUT ;
    USE SIGNAL ;
    SHAPE ABUTMENT ;
    PORT
      LAYER met2 ;
      RECT 110.790 233.500 110.930 233.920 ;
    END
  END rw0_rd_out[47]
  PIN rw0_rd_out[48]
    DIRECTION OUTPUT ;
    USE SIGNAL ;
    SHAPE ABUTMENT ;
    PORT
      LAYER met2 ;
      RECT 113.090 233.500 113.230 233.920 ;
    END
  END rw0_rd_out[48]
  PIN rw0_rd_out[49]
    DIRECTION OUTPUT ;
    USE SIGNAL ;
    SHAPE ABUTMENT ;
    PORT
      LAYER met2 ;
      RECT 115.390 233.500 115.530 233.920 ;
    END
  END rw0_rd_out[49]
  PIN rw0_rd_out[50]
    DIRECTION OUTPUT ;
    USE SIGNAL ;
    SHAPE ABUTMENT ;
    PORT
      LAYER met2 ;
      RECT 117.690 233.500 117.830 233.920 ;
    END
  END rw0_rd_out[50]
  PIN rw0_rd_out[51]
    DIRECTION OUTPUT ;
    USE SIGNAL ;
    SHAPE ABUTMENT ;
    PORT
      LAYER met2 ;
      RECT 119.990 233.500 120.130 233.920 ;
    END
  END rw0_rd_out[51]
  PIN rw0_rd_out[52]
    DIRECTION OUTPUT ;
    USE SIGNAL ;
    SHAPE ABUTMENT ;
    PORT
      LAYER met2 ;
      RECT 122.290 233.500 122.430 233.920 ;
    END
  END rw0_rd_out[52]
  PIN rw0_rd_out[53]
    DIRECTION OUTPUT ;
    USE SIGNAL ;
    SHAPE ABUTMENT ;
    PORT
      LAYER met2 ;
      RECT 124.590 233.500 124.730 233.920 ;
    END
  END rw0_rd_out[53]
  PIN rw0_rd_out[54]
    DIRECTION OUTPUT ;
    USE SIGNAL ;
    SHAPE ABUTMENT ;
    PORT
      LAYER met2 ;
      RECT 126.890 233.500 127.030 233.920 ;
    END
  END rw0_rd_out[54]
  PIN rw0_rd_out[55]
    DIRECTION OUTPUT ;
    USE SIGNAL ;
    SHAPE ABUTMENT ;
    PORT
      LAYER met2 ;
      RECT 129.190 233.500 129.330 233.920 ;
    END
  END rw0_rd_out[55]
  PIN rw0_rd_out[56]
    DIRECTION OUTPUT ;
    USE SIGNAL ;
    SHAPE ABUTMENT ;
    PORT
      LAYER met2 ;
      RECT 131.490 233.500 131.630 233.920 ;
    END
  END rw0_rd_out[56]
  PIN rw0_rd_out[57]
    DIRECTION OUTPUT ;
    USE SIGNAL ;
    SHAPE ABUTMENT ;
    PORT
      LAYER met2 ;
      RECT 133.790 233.500 133.930 233.920 ;
    END
  END rw0_rd_out[57]
  PIN rw0_rd_out[58]
    DIRECTION OUTPUT ;
    USE SIGNAL ;
    SHAPE ABUTMENT ;
    PORT
      LAYER met2 ;
      RECT 136.090 233.500 136.230 233.920 ;
    END
  END rw0_rd_out[58]
  PIN rw0_rd_out[59]
    DIRECTION OUTPUT ;
    USE SIGNAL ;
    SHAPE ABUTMENT ;
    PORT
      LAYER met2 ;
      RECT 138.390 233.500 138.530 233.920 ;
    END
  END rw0_rd_out[59]
  PIN rw0_rd_out[60]
    DIRECTION OUTPUT ;
    USE SIGNAL ;
    SHAPE ABUTMENT ;
    PORT
      LAYER met2 ;
      RECT 140.690 233.500 140.830 233.920 ;
    END
  END rw0_rd_out[60]
  PIN rw0_rd_out[61]
    DIRECTION OUTPUT ;
    USE SIGNAL ;
    SHAPE ABUTMENT ;
    PORT
      LAYER met2 ;
      RECT 142.990 233.500 143.130 233.920 ;
    END
  END rw0_rd_out[61]
  PIN rw0_rd_out[62]
    DIRECTION OUTPUT ;
    USE SIGNAL ;
    SHAPE ABUTMENT ;
    PORT
      LAYER met2 ;
      RECT 145.290 233.500 145.430 233.920 ;
    END
  END rw0_rd_out[62]
  PIN rw0_rd_out[63]
    DIRECTION OUTPUT ;
    USE SIGNAL ;
    SHAPE ABUTMENT ;
    PORT
      LAYER met2 ;
      RECT 147.590 233.500 147.730 233.920 ;
    END
  END rw0_rd_out[63]
  PIN rw0_addr_in[0]
    DIRECTION INPUT ;
    USE SIGNAL ;
    SHAPE ABUTMENT ;
    PORT
      LAYER met3 ;
      RECT 0.000 199.770 0.900 200.070 ;
    END
  END rw0_addr_in[0]
  PIN rw0_addr_in[1]
    DIRECTION INPUT ;
    USE SIGNAL ;
    SHAPE ABUTMENT ;
    PORT
      LAYER met3 ;
      RECT 0.000 205.890 0.900 206.190 ;
    END
  END rw0_addr_in[1]
  PIN rw0_addr_in[2]
    DIRECTION INPUT ;
    USE SIGNAL ;
    SHAPE ABUTMENT ;
    PORT
      LAYER met3 ;
      RECT 0.000 212.010 0.900 212.310 ;
    END
  END rw0_addr_in[2]
  PIN rw0_addr_in[3]
    DIRECTION INPUT ;
    USE SIGNAL ;
    SHAPE ABUTMENT ;
    PORT
      LAYER met3 ;
      RECT 189.080 199.770 189.980 200.070 ;
    END
  END rw0_addr_in[3]
  PIN rw0_addr_in[4]
    DIRECTION INPUT ;
    USE SIGNAL ;
    SHAPE ABUTMENT ;
    PORT
      LAYER met3 ;
      RECT 189.080 205.890 189.980 206.190 ;
    END
  END rw0_addr_in[4]
  PIN rw0_addr_in[5]
    DIRECTION INPUT ;
    USE SIGNAL ;
    SHAPE ABUTMENT ;
    PORT
      LAYER met3 ;
      RECT 189.080 212.010 189.980 212.310 ;
    END
  END rw0_addr_in[5]
  PIN rw0_we_in
    DIRECTION INPUT ;
    USE SIGNAL ;
    SHAPE ABUTMENT ;
    PORT
      LAYER met2 ;
      RECT 149.890 233.500 150.030 233.920 ;
    END
  END rw0_we_in
  PIN rw0_ce_in
    DIRECTION INPUT ;
    USE SIGNAL ;
    SHAPE ABUTMENT ;
    PORT
      LAYER met2 ;
      RECT 152.190 233.500 152.330 233.920 ;
    END
  END rw0_ce_in
  PIN rw0_clk
    DIRECTION INPUT ;
    USE SIGNAL ;
    SHAPE ABUTMENT ;
    PORT
      LAYER met2 ;
      RECT 154.490 233.500 154.630 233.920 ;
    END
  END rw0_clk
  PIN VSS
    DIRECTION INOUT ;
    USE GROUND ;
    PORT
      LAYER met4 ;
      RECT 2.160 4.080 3.360 229.840 ;
      RECT 13.040 4.080 14.240 229.840 ;
      RECT 23.920 4.080 25.120 229.840 ;
      RECT 34.800 4.080 36.000 229.840 ;
      RECT 45.680 4.080 46.880 229.840 ;
      RECT 56.560 4.080 57.760 229.840 ;
      RECT 67.440 4.080 68.640 229.840 ;
      RECT 78.320 4.080 79.520 229.840 ;
      RECT 89.200 4.080 90.400 229.840 ;
      RECT 100.080 4.080 101.280 229.840 ;
      RECT 110.960 4.080 112.160 229.840 ;
      RECT 121.840 4.080 123.040 229.840 ;
      RECT 132.720 4.080 133.920 229.840 ;
      RECT 143.600 4.080 144.800 229.840 ;
      RECT 154.480 4.080 155.680 229.840 ;
      RECT 165.360 4.080 166.560 229.840 ;
      RECT 176.240 4.080 177.440 229.840 ;
      RECT 187.120 4.080 188.320 229.840 ;
    END
  END VSS
  PIN VDD
    DIRECTION INOUT ;
    USE POWER ;
    PORT
      LAYER met4 ;
      RECT 2.160 4.080 3.360 229.840 ;
      RECT 13.040 4.080 14.240 229.840 ;
      RECT 23.920 4.080 25.120 229.840 ;
      RECT 34.800 4.080 36.000 229.840 ;
      RECT 45.680 4.080 46.880 229.840 ;
      RECT 56.560 4.080 57.760 229.840 ;
      RECT 67.440 4.080 68.640 229.840 ;
      RECT 78.320 4.080 79.520 229.840 ;
      RECT 89.200 4.080 90.400 229.840 ;
      RECT 100.080 4.080 101.280 229.840 ;
      RECT 110.960 4.080 112.160 229.840 ;
      RECT 121.840 4.080 123.040 229.840 ;
      RECT 132.720 4.080 133.920 229.840 ;
      RECT 143.600 4.080 144.800 229.840 ;
      RECT 154.480 4.080 155.680 229.840 ;
      RECT 165.360 4.080 166.560 229.840 ;
      RECT 176.240 4.080 177.440 229.840 ;
      RECT 187.120 4.080 188.320 229.840 ;
    END
  END VDD
  OBS
    LAYER met1 ;
    RECT 0 0 189.980 233.920 ;
    LAYER met2 ;
    RECT 0 0 189.980 233.920 ;
    LAYER met3 ;
    RECT 0 0 189.980 233.920 ;
    LAYER met4 ;
    RECT 0 0 189.980 233.920 ;
  END
END fakeram_64x64_1rw

END LIBRARY
